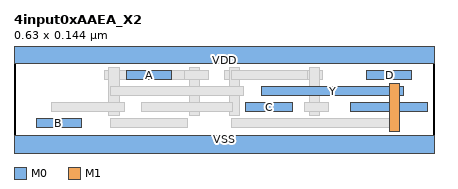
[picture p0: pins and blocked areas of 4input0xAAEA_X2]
MACRO 4input0xAAEA_X2
  CLASS CORE ;
  ORIGIN 0 0 ;
  FOREIGN 4input0xAAEA_X2 0 0 ;
  SIZE 0.6300 BY 0.1440 ;
  SYMMETRY X Y ;
  SITE coresite ;
  PIN A
    DIRECTION INPUT ;
    USE SIGNAL ;
    PORT
      LAYER M0 ;
        RECT 0.1680 0.1010 0.2370 0.1150 ;
    END
  END A
  PIN B
    DIRECTION INPUT ;
    USE SIGNAL ;
    PORT
      LAYER M0 ;
        RECT 0.0330 0.0290 0.1020 0.0430 ;
    END
  END B
  PIN C
    DIRECTION INPUT ;
    USE SIGNAL ;
    PORT
      LAYER M0 ;
        RECT 0.3480 0.0530 0.4170 0.0670 ;
    END
  END C
  PIN D
    DIRECTION INPUT ;
    USE SIGNAL ;
    PORT
      LAYER M0 ;
        RECT 0.5280 0.1010 0.5970 0.1150 ;
    END
  END D
  PIN Y
    DIRECTION OUTPUT ;
    USE SIGNAL ;
    PORT
      LAYER M1 ;
        RECT 0.5625 0.0240 0.5775 0.0960 ;
      LAYER M0 ;
        RECT 0.3705 0.0770 0.5850 0.0910 ;
        RECT 0.5055 0.0530 0.6195 0.0670 ;
    END
  END Y
  PIN VDD
    DIRECTION INOUT ;
    USE POWER ;
    SHAPE ABUTMENT ;
    PORT
      LAYER M0 ;
        RECT 0.0000 0.1260 0.6300 0.1620 ;
    END
  END VDD
  PIN VSS
    DIRECTION INOUT ;
    USE GROUND ;
    SHAPE ABUTMENT ;
    PORT
      LAYER M0 ;
        RECT 0.0000 -0.0180 0.6300 0.0180 ;
    END
  END VSS
  OBS
    LAYER M2 ;
      RECT 0.1350 0.1010 0.2820 0.1150 ;
      RECT 0.3150 0.1010 0.4620 0.1150 ;
    LAYER V1 ;
      RECT 0.3230 0.1010 0.3370 0.1150 ;
      RECT 0.4430 0.1010 0.4570 0.1150 ;
      RECT 0.1430 0.1010 0.1570 0.1150 ;
      RECT 0.2630 0.1010 0.2770 0.1150 ;
    LAYER M1 ;
      RECT 0.1425 0.0480 0.1575 0.1200 ;
      RECT 0.2625 0.0480 0.2775 0.1200 ;
      RECT 0.3225 0.0480 0.3375 0.1200 ;
      RECT 0.4425 0.0480 0.4575 0.1200 ;
    LAYER V0 ;
      RECT 0.3230 0.0770 0.3370 0.0910 ;
      RECT 0.4430 0.0530 0.4570 0.0670 ;
      RECT 0.5630 0.0770 0.5770 0.0910 ;
      RECT 0.5630 0.0530 0.5770 0.0670 ;
      RECT 0.1430 0.0530 0.1570 0.0670 ;
      RECT 0.2630 0.1010 0.2770 0.1150 ;
    LAYER M0 ;
      RECT 0.1455 0.0290 0.2595 0.0430 ;
      RECT 0.3255 0.0290 0.5745 0.0430 ;
      RECT 0.0555 0.0530 0.1650 0.0670 ;
      RECT 0.1905 0.0530 0.3270 0.0670 ;
      RECT 0.4350 0.0530 0.4725 0.0670 ;
      RECT 0.1455 0.0770 0.3450 0.0910 ;
      RECT 0.2550 0.1010 0.2925 0.1150 ;
      RECT 0.3255 0.1010 0.4395 0.1150 ;
  END
END 4input0xAAEA_X2
